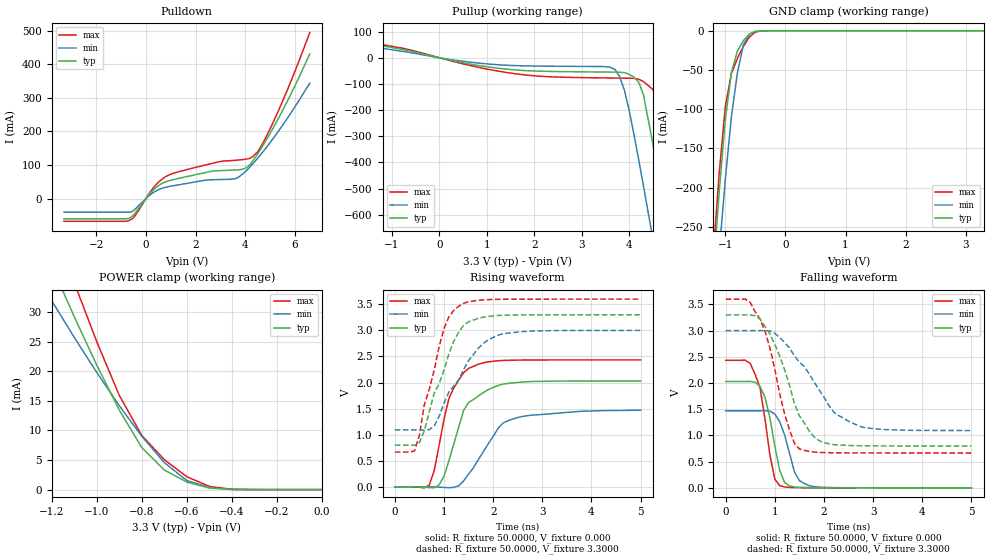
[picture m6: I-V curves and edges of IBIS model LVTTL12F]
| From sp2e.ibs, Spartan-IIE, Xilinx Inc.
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|   Model LVTTL12F
[Model]   LVTTL12F
Model_type   I/O
Polarity   Non-Inverting
Enable   Active-Low
Vinl =   0.800V
Vinh =   2.000V
Vmeas =   1.4000V
Cref =  35.0000pF
Rref =   1.0000M
Vref =  0.000V
C_comp   5.0000pF   4.0000pF   6.0000pF
[Temperature Range]   25.0000   100.0000   0.000
[Voltage Range]   3.3000V   3.0000V   3.6000V
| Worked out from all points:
|   slope of the pulldown table from 0 to 0.495 V, typ, clamps not added: 13 ohm
|   slope of the pullup table from 0 to 0.495 V, typ, clamps not added: 26.2 ohm
|   GND clamp passes 1 mA (typ) near -0.51 V on its own axis
|   POWER clamp passes 1 mA (typ) near -0.57 V on its own axis
|   rising waveform, R_fixture 50.0000, V_fixture 0.000: 20-80 % time 443ps typ, 612ps min, 396ps max; typ from 0 V to 2.03 V
|   rising waveform, R_fixture 50.0000, V_fixture 3.3000: 20-80 % time 541ps typ, 717ps min, 449ps max; typ from 0.798 V to 3.3 V
|   falling waveform, R_fixture 50.0000, V_fixture 0.000: 20-80 % time 257ps typ, 269ps min, 247ps max; typ from 2.03 V to 0 V
|   falling waveform, R_fixture 50.0000, V_fixture 3.3000: 20-80 % time 588ps typ, 843ps min, 461ps max; typ from 3.3 V to 0.799 V
[Pulldown]
| voltage   I(typ)   I(min)   I(max)
-3.3V     -60.15mA   -40.41mA   -67.67mA
-700mV    -58.89mA   -40.41mA   -65.55mA
-500mV    -48.76mA   -35.67mA   -56.93mA
300mV     26mA       18mA       32.25mA
900mV     52.59mA    35.53mA    69.58mA
3.6V      85.3mA     59.32mA    114.1mA
4V        90.58mA    80.11mA    117.1mA
4.3V      111.5mA    103.1mA    124.9mA
4.5V      132.9mA    120.1mA    139mA
5.1V      207mA      176.5mA    223.3mA
5.9V      320.5mA    261.9mA    360.1mA
6.6V      430.7mA    344mA      494.6mA
[Pullup]
| voltage   I(typ)   I(min)   I(max)
-3.3V     107.1mA    98.2mA     107.1mA
1.1V      -36.77mA   -24.77mA   -46.5mA
3.6V      -54.57mA   -35.95mA   -77.25mA
3.8V      -55.05mA   -72.48mA   -77.68mA
4V        -63.12mA   -202mA     -78.1mA
4.2V      -93.01mA   -389.3mA   -81.74mA
4.3V      -141.5mA   -489mA     -90.74mA
4.5V      -329.4mA   -693.2mA   -121.1mA
4.7V      -548.5mA   -901.1mA   -218.8mA
4.9V      -775.5mA   -1.111A    -428mA
5.1V      -1.006A    -1.322A    -657.9mA
6.6V      -2.771A    -2.929A    -2.47A
[GND_clamp]
| voltage   I(typ)   I(min)   I(max)
-3.3V     -2.749A    -2.594A    -2.805A
-1.2V     -306mA     -377.1mA   -282.7mA
-1.1V     -202.5mA   -280mA     -178.8mA
-1V       -112.5mA   -188.5mA   -95.98mA
-900mV    -53.5mA    -109.7mA   -54.53mA
-800mV    -25.67mA   -53.59mA   -35.13mA
-700mV    -12.44mA   -17.88mA   -19.82mA
-600mV    -3.982mA   -4.202mA   -7.865mA
-500mV    -601.5uA   -800.3uA   -1.508mA
-400mV    -51.05uA   -119.3uA   -124.3uA
3.3V      18.74nA    3.634uA    18.92nA
[POWER_clamp]
| voltage   I(typ)   I(min)   I(max)
-3.3V     237mA      175.9mA    284.4mA
-1.3V     46.69mA    38.29mA    56.33mA
-1.2V     37.79mA    31.9mA     45.45mA
-1.1V     29.2mA     25.71mA    34.95mA
-1V       21.01mA    19.78mA    24.97mA
-900mV    13.43mA    14.17mA    15.91mA
-800mV    7.091mA    8.993mA    9.139mA
-700mV    3.305mA    4.554mA    5.052mA
-600mV    1.265mA    1.529mA    2.172mA
-500mV    263.8uA    333.6uA    531.5uA
-400mV    22.63uA    44.12uA    49.77uA
0V        18.8nA     17.88nA    22.53nA
[Ramp]
| variable   typ   min   max
dV/dt_r   1.2180/0.4621n   0.8808/0.6275n   1.4604/0.3920n
dV/dt_f   1.5008/0.5942n   1.1442/0.8735n   1.7606/0.4564n
R_load = 50.0000
[Rising Waveform]
R_fixture = 50.0000
V_fixture = 0.000
| time   V(typ)   V(min)   V(max)
0s        1.805uV    2.104uV    1.747uV
700ps     -15.84mV   19.6uV     30.49mV
800ps     -18.73mV   -2.787mV   307.3mV
900ps     35.45mV    -6.717mV   788.3mV
1.1ns     499.2mV    -18.35mV   1.694V
1.4ns     1.467V     114.6mV    2.189V
1.5ns     1.617V     242.7mV    2.271V
2.1ns     1.944V     1.118V     2.418V
2.3ns     1.983V     1.266V     2.426V
5ns       2.03V      1.468V     2.434V
[Rising Waveform]
R_fixture = 50.0000
V_fixture = 3.3000
V_fixture_min = 3.0000
V_fixture_max = 3.6000
| time   V(typ)   V(min)   V(max)
0s        798mV      1.091V     665.3mV
400ps     796.4mV    1.091V     687.4mV
500ps     845.9mV    1.091V     988.9mV
600ps     1.077V     1.088V     1.575V
800ps     1.794V     1.163V     2.235V
1ns       2.237V     1.603V     3.036V
1.4ns     3.1V       2.249V     3.521V
1.8ns     3.253V     2.751V     3.586V
2.2ns     3.292V     2.934V     3.598V
5ns       3.3V       3V         3.6V
[Falling Waveform]
R_fixture = 50.0000
V_fixture = 0.000
| time   V(typ)   V(min)   V(max)
0s        2.03V      1.471V     2.434V
400ps     2.03V      1.471V     2.435V
600ps     2.014V     1.471V     2.164V
700ps     1.938V     1.471V     1.905V
800ps     1.728V     1.472V     1.313V
1ns       799mV      1.408V     164.7mV
1.1ns     330.1mV    1.262V     41.78mV
1.4ns     15.16mV    298.9mV    5.664mV
1.7ns     5.083mV    42.62mV    2.608mV
5ns       247.7uV    403.5uV    122.9uV
[Falling Waveform]
R_fixture = 50.0000
V_fixture = 3.3000
V_fixture_min = 3.0000
V_fixture_max = 3.6000
| time   V(typ)   V(min)   V(max)
0s        3.3V       3V         3.6V
400ps     3.3V       3V         3.601V
700ps     3.217V     3V         3.221V
900ps     2.931V     2.994V     2.672V
1.2ns     2.248V     2.773V     1.405V
1.5ns     1.376V     2.398V     742.6mV
1.9ns     900.3mV    1.871V     677mV
2.2ns     824.9mV    1.443V     669.1mV
2.7ns     804.3mV    1.185V     666.8mV
5ns       798.7mV    1.093V     665.6mV
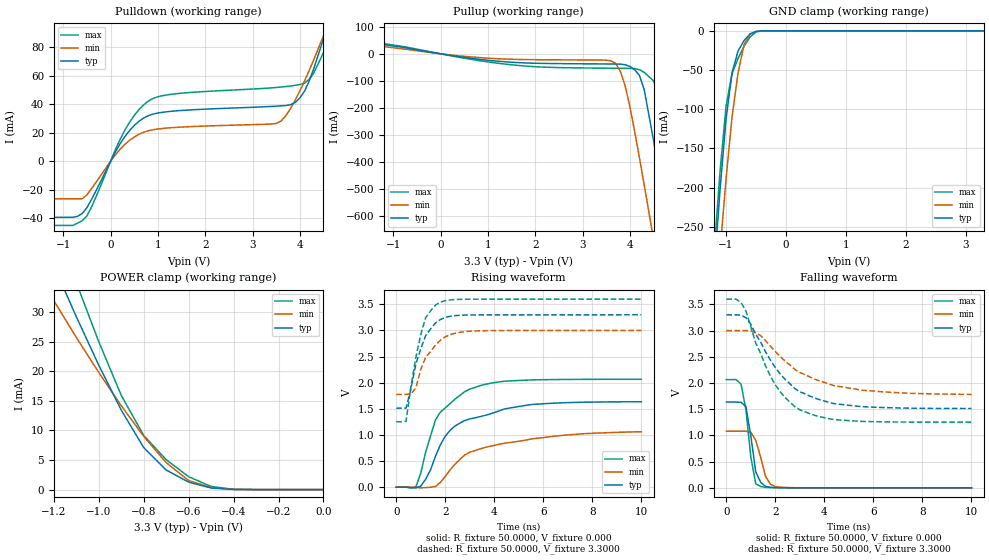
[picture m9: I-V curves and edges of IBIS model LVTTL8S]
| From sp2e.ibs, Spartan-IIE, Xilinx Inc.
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|   Model LVTTL8S
[Model]   LVTTL8S
Model_type   I/O
Polarity   Non-Inverting
Enable   Active-Low
Vinl =   0.800V
Vinh =   2.000V
Vmeas =   1.4000V
Cref =  35.0000pF
Rref =   1.0000M
Vref =  0.000V
C_comp   5.0000pF   4.0000pF   6.0000pF
[Temperature Range]   25.0000   100.0000   0.000
[Voltage Range]   3.3000V   3.0000V   3.6000V
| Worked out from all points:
|   slope of the pulldown table from 0 to 0.495 V, typ, clamps not added: 19.8 ohm
|   slope of the pullup table from 0 to 0.495 V, typ, clamps not added: 37.6 ohm
|   GND clamp passes 1 mA (typ) near -0.51 V on its own axis
|   POWER clamp passes 1 mA (typ) near -0.57 V on its own axis
|   rising waveform, R_fixture 50.0000, V_fixture 0.000: 20-80 % time 1.62ns typ, 2.52ns min, 1.25ns max; typ from 0 V to 1.64 V
|   rising waveform, R_fixture 50.0000, V_fixture 3.3000: 20-80 % time 671ps typ, 802ps min, 591ps max; typ from 1.51 V to 3.3 V
|   falling waveform, R_fixture 50.0000, V_fixture 0.000: 20-80 % time 308ps typ, 375ps min, 334ps max; typ from 1.64 V to 0 V
|   falling waveform, R_fixture 50.0000, V_fixture 3.3000: 20-80 % time 1.69ns typ, 2.2ns min, 1.44ns max; typ from 3.3 V to 1.51 V
[Pulldown]
| voltage   I(typ)   I(min)   I(max)
-3.3V     -39.4mA    -26.4mA    -45.12mA
-800mV    -39.4mA    -26.4mA    -45.12mA
-500mV    -32.62mA   -23.56mA   -38.41mA
300mV     17.27mA    11.77mA    21.73mA
800mV     32.1mA     21.46mA    42.37mA
1.4V      35.46mA    23.84mA    47.52mA
3.5V      38.73mA    26.63mA    51.86mA
3.9V      41.29mA    42.86mA    53.39mA
4.2V      56.65mA    64.01mA    57.69mA
4.5V      86.17mA    88.28mA    76.45mA
4.7V      108.4mA    105.6mA    100mA
6.6V      357.5mA    296.7mA    396mA
[Pullup]
| voltage   I(typ)   I(min)   I(max)
-3.3V     88.6mA     82.8mA     87.5mA
1V        -23.82mA   -16.13mA   -29.99mA
3.6V      -37.7mA    -26.01mA   -53.41mA
3.8V      -38.18mA   -66.39mA   -53.7mA
3.9V      -40.39mA   -120.1mA   -53.85mA
4.2V      -80.09mA   -385.5mA   -58.68mA
4.3V      -132.2mA   -485.2mA   -68.69mA
4.5V      -322.1mA   -689.5mA   -100.2mA
4.7V      -541.6mA   -897.5mA   -206mA
4.9V      -768.7mA   -1.107A    -417.4mA
5.1V      -999.4mA   -1.319A    -647.8mA
6.6V      -2.764A    -2.926A    -2.46A
[GND_clamp]
| voltage   I(typ)   I(min)   I(max)
-3.3V     -2.749A    -2.594A    -2.804A
-1.2V     -306mA     -377.1mA   -282.7mA
-1.1V     -202.5mA   -280mA     -178.8mA
-1V       -112.5mA   -188.5mA   -95.98mA
-900mV    -53.5mA    -109.7mA   -54.53mA
-800mV    -25.67mA   -53.59mA   -35.13mA
-700mV    -12.44mA   -17.88mA   -19.82mA
-600mV    -3.982mA   -4.202mA   -7.865mA
-500mV    -601.5uA   -800.3uA   -1.508mA
-400mV    -51.05uA   -119.3uA   -124.3uA
3.3V      18.74nA    3.634uA    18.92nA
[POWER_clamp]
| voltage   I(typ)   I(min)   I(max)
-3.3V     237mA      175.9mA    284.4mA
-1.3V     46.69mA    38.29mA    56.33mA
-1.2V     37.79mA    31.9mA     45.45mA
-1.1V     29.2mA     25.71mA    34.95mA
-1V       21.01mA    19.78mA    24.97mA
-900mV    13.43mA    14.17mA    15.91mA
-800mV    7.091mA    8.993mA    9.139mA
-700mV    3.305mA    4.554mA    5.052mA
-600mV    1.265mA    1.529mA    2.172mA
-500mV    263.8uA    333.6uA    531.5uA
-400mV    22.63uA    44.12uA    49.77uA
0V        18.8nA     38.36nA    22.53nA
[Ramp]
| variable   typ   min   max
dV/dt_r   0.9810/1.6620n   0.6366/2.5875n   1.2390/1.1845n
dV/dt_f   1.0716/1.6786n   0.7302/2.1970n   1.4082/1.3868n
R_load = 50.0000
[Rising Waveform]
R_fixture = 50.0000
V_fixture = 0.000
| time   V(typ)   V(min)   V(max)
0s        2.224uV    2.595uV    2.141uV
800ps     -12.52mV   -5.336mV   4.282mV
1ns       18.45mV    -12.04mV   265.1mV
1.2ns     151.7mV    -8.508mV   670.3mV
1.6ns     588.6mV    14.18mV    1.287V
2.2ns     1.09V      330.8mV    1.602V
3ns       1.307V     669.8mV    1.877V
4.2ns     1.462V     820.9mV    2.016V
5.6ns     1.585V     929.6mV    2.054V
10ns      1.635V     1.061V     2.065V
[Rising Waveform]
R_fixture = 50.0000
V_fixture = 3.3000
V_fixture_min = 3.0000
V_fixture_max = 3.6000
| time   V(typ)   V(min)   V(max)
0s        1.513V     1.776V     1.252V
400ps     1.512V     1.776V     1.26V
600ps     1.88V      1.783V     1.922V
800ps     2.355V     1.896V     2.48V
1ns       2.646V     2.25V      2.919V
1.2ns     2.9V       2.484V     3.244V
1.8ns     3.209V     2.813V     3.542V
2.2ns     3.272V     2.92V      3.585V
3ns       3.297V     2.986V     3.598V
10ns      3.3V       2.999V     3.6V
[Falling Waveform]
R_fixture = 50.0000
V_fixture = 0.000
| time   V(typ)   V(min)   V(max)
0s        1.637V     1.08V      2.065V
400ps     1.637V     1.08V      2.066V
600ps     1.633V     1.08V      1.977V
800ps     1.551V     1.081V     1.491V
1ns       990.3mV    1.062V     583.9mV
1.2ns     306.2mV    906.8mV    79.03mV
1.4ns     105.5mV    581.7mV    26.33mV
1.6ns     27.38mV    217.1mV    9.177mV
2ns       6.009mV    24.5mV     3.195mV
10ns      146.7uV    152.9uV    84.37uV
[Falling Waveform]
R_fixture = 50.0000
V_fixture = 3.3000
V_fixture_min = 3.0000
V_fixture_max = 3.6000
| time   V(typ)   V(min)   V(max)
0s        3.3V       3V         3.6V
600ps     3.296V     3V         3.534V
800ps     3.245V     3V         3.375V
1ns       3.12V      2.993V     3.07V
1.2ns     2.931V     2.954V     2.762V
1.8ns     2.434V     2.701V     2.129V
2.4ns     2.068V     2.417V     1.722V
3ns       1.833V     2.2V       1.489V
5.6ns     1.547V     1.861V     1.267V
10ns      1.514V     1.783V     1.253V
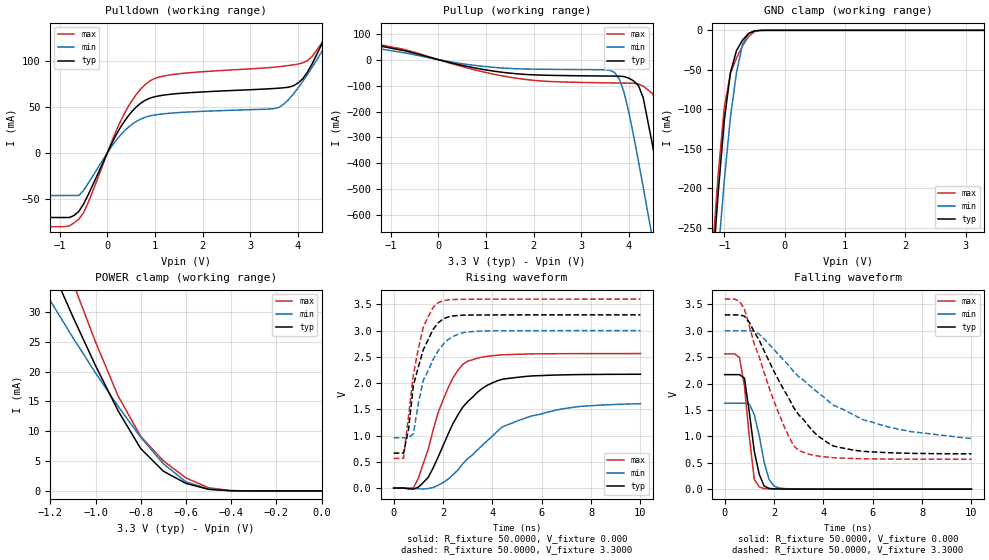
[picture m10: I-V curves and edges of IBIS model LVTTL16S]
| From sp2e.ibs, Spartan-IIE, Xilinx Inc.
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|   Model LVTTL16S
[Model]   LVTTL16S
Model_type   I/O
Polarity   Non-Inverting
Enable   Active-Low
Vinl =   0.800V
Vinh =   2.000V
Vmeas =   1.4000V
Cref =  35.0000pF
Rref =   1.0000M
Vref =  0.000V
C_comp   5.0000pF   4.0000pF   6.0000pF
[Temperature Range]   25.0000   100.0000   0.000
[Voltage Range]   3.3000V   3.0000V   3.6000V
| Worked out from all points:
|   slope of the pulldown table from 0 to 0.495 V, typ, clamps not added: 11.3 ohm
|   slope of the pullup table from 0 to 0.495 V, typ, clamps not added: 22.7 ohm
|   GND clamp passes 1 mA (typ) near -0.51 V on its own axis
|   POWER clamp passes 1 mA (typ) near -0.57 V on its own axis
|   rising waveform, R_fixture 50.0000, V_fixture 0.000: 20-80 % time 1.56ns typ, 2.5ns min, 1.12ns max; typ from 0 V to 2.17 V
|   rising waveform, R_fixture 50.0000, V_fixture 3.3000: 20-80 % time 725ps typ, 858ps min, 614ps max; typ from 0.666 V to 3.3 V
|   falling waveform, R_fixture 50.0000, V_fixture 0.000: 20-80 % time 418ps typ, 459ps min, 354ps max; typ from 2.17 V to 0 V
|   falling waveform, R_fixture 50.0000, V_fixture 3.3000: 20-80 % time 1.95ns typ, 3.28ns min, 1.37ns max; typ from 3.3 V to 0.669 V
[Pulldown]
| voltage   I(typ)   I(min)   I(max)
-3.3V     -70.66mA   -46.65mA   -80.67mA
-700mV    -68.43mA   -46.65mA   -76.48mA
-500mV    -55.91mA   -40.95mA   -65.29mA
400mV     37.55mA    25.93mA    46.88mA
700mV     54.05mA    36.76mA    69.52mA
1V        61.15mA    41.22mA    81.1mA
3.6V      70.43mA    49.47mA    93.83mA
4.1V      80.53mA    77.58mA    97.93mA
4.3V      97.01mA    93.21mA    105mA
4.7V      141.4mA    127.9mA    144.1mA
4.9V      166mA      146.6mA    172.8mA
6.6V      410.5mA    330.4mA    469.3mA
[Pullup]
| voltage   I(typ)   I(min)   I(max)
-3.3V     116.8mA    106.3mA    117.5mA
1.2V      -45.24mA   -30.27mA   -57.51mA
3.6V      -63.32mA   -41.14mA   -89.59mA
3.8V      -63.82mA   -75.74mA   -90.08mA
3.9V      -65.44mA   -127.4mA   -90.31mA
4.2V      -99.96mA   -391.3mA   -93.78mA
4.3V      -146.5mA   -490.9mA   -102.2mA
4.5V      -333.2mA   -695.1mA   -132.1mA
4.7V      -552mA     -903mA     -225.7mA
4.9V      -779mA     -1.113A    -433.5mA
5.1V      -1.009A    -1.324A    -663.2mA
6.6V      -2.775A    -2.931A    -2.475A
[GND_clamp]
| voltage   I(typ)   I(min)   I(max)
-3.3V     -2.749A    -2.594A    -2.805A
-1.2V     -306mA     -377.1mA   -282.7mA
-1.1V     -202.5mA   -280mA     -178.8mA
-1V       -112.5mA   -188.5mA   -95.98mA
-900mV    -53.5mA    -109.7mA   -54.53mA
-800mV    -25.67mA   -53.59mA   -35.13mA
-700mV    -12.44mA   -17.88mA   -19.82mA
-600mV    -3.982mA   -4.202mA   -7.865mA
-500mV    -601.5uA   -800.3uA   -1.508mA
-400mV    -51.05uA   -119.3uA   -124.3uA
3.3V      18.74nA    3.634uA    18.92nA
[POWER_clamp]
| voltage   I(typ)   I(min)   I(max)
-3.3V     237mA      175.9mA    284.4mA
-1.3V     46.69mA    38.29mA    56.33mA
-1.2V     37.79mA    31.9mA     45.45mA
-1.1V     29.2mA     25.71mA    34.95mA
-1V       21.01mA    19.78mA    24.97mA
-900mV    13.43mA    14.17mA    15.91mA
-800mV    7.091mA    8.993mA    9.139mA
-700mV    3.305mA    4.554mA    5.052mA
-600mV    1.265mA    1.529mA    2.172mA
-500mV    263.8uA    333.6uA    531.5uA
-400mV    22.63uA    44.12uA    49.77uA
0V        18.8nA     38.3nA     22.53nA
[Ramp]
| variable   typ   min   max
dV/dt_r   1.3008/1.5553n   0.9642/2.4921n   1.5372/1.0670n
dV/dt_f   1.5787/1.9536n   1.2001/3.1912n   1.8204/1.3154n
R_load = 50.0000
[Rising Waveform]
R_fixture = 50.0000
V_fixture = 0.000
| time   V(typ)   V(min)   V(max)
0s        1.565uV    1.815uV    1.522uV
800ps     -20.61mV   -3.077mV   4.223mV
1.4ns     205mV      -9.034mV   736.4mV
1.8ns     588.3mV    53.46mV    1.433V
2.2ns     1.02V      168.2mV    1.899V
2.6ns     1.391V     342.4mV    2.24V
3ns       1.647V     561.3mV    2.416V
4.2ns     2.043V     1.082V     2.531V
5.6ns     2.136V     1.373V     2.555V
10ns      2.168V     1.607V     2.562V
[Rising Waveform]
R_fixture = 50.0000
V_fixture = 3.3000
V_fixture_min = 3.0000
V_fixture_max = 3.6000
| time   V(typ)   V(min)   V(max)
0s        666.2mV    958.1mV    565.5mV
400ps     665.7mV    958.2mV    568.9mV
600ps     1.112V     957.8mV    1.362V
800ps     1.956V     1.035V     2.167V
1.2ns     2.633V     2.054V     3.063V
1.6ns     3.023V     2.449V     3.442V
1.8ns     3.146V     2.612V     3.53V
2.4ns     3.277V     2.886V     3.591V
3ns       3.295V     2.974V     3.596V
10ns      3.3V       2.999V     3.6V
[Falling Waveform]
R_fixture = 50.0000
V_fixture = 0.000
| time   V(typ)   V(min)   V(max)
0s        2.169V     1.627V     2.562V
600ps     2.169V     1.627V     2.493V
800ps     2.102V     1.628V     1.951V
1ns       1.447V     1.61V      985.2mV
1.2ns     715.7mV    1.409V     184mV
1.4ns     280.9mV    1.012V     43.42mV
1.6ns     58.04mV    508.7mV    9.87mV
1.8ns     14.69mV    184mV      5.394mV
2.2ns     4.424mV    23.52mV    2.301mV
10ns      82.54uV    150.6uV    57.71uV
[Falling Waveform]
R_fixture = 50.0000
V_fixture = 3.3000
V_fixture_min = 3.0000
V_fixture_max = 3.6000
| time   V(typ)   V(min)   V(max)
0s        3.3V       3V         3.6V
800ps     3.276V     3V         3.409V
1.4ns     2.821V     2.935V     2.506V
2ns       2.232V     2.643V     1.663V
2.6ns     1.722V     2.341V     995.5mV
3ns       1.408V     2.129V     733.6mV
3.8ns     1V         1.822V     626.9mV
4.6ns     795.9mV    1.55V      591.8mV
6.8ns     688mV      1.161V     569.8mV
10ns      668.9mV    960mV      566mV
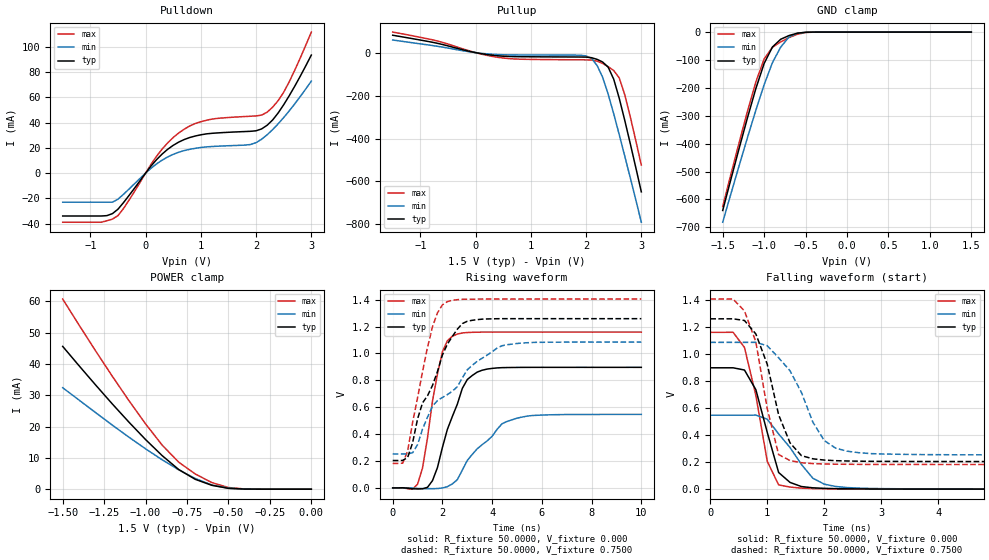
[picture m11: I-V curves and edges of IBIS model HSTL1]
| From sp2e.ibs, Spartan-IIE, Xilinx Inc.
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|   Model HSTL1
[Model]   HSTL1
Model_type   I/O
Polarity   Non-Inverting
Enable   Active-Low
Vinl =   0.650V
Vinh =   0.850V
Vmeas =   0.7500V
Cref =  20.0000pF
Rref =  50.0000
Vref =   0.7500V
C_comp   5.0000pF   4.0000pF   6.0000pF
[Temperature Range]   25.0000   100.0000   0.000
[Voltage Range]   1.5000V   1.4000V   1.6000V
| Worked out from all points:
|   slope of the pulldown table from 0 to 0.225 V, typ, clamps not added: 19 ohm
|   slope of the pullup table from 0 to 0.225 V, typ, clamps not added: 23.5 ohm
|   GND clamp passes 1 mA (typ) near -0.51 V on its own axis
|   POWER clamp passes 1 mA (typ) near -0.58 V on its own axis
|   rising waveform, R_fixture 50.0000, V_fixture 0.000: 20-80 % time 924ps typ, 1.47ns min, 622ps max; typ from 0 V to 0.897 V
|   rising waveform, R_fixture 50.0000, V_fixture 0.7500: 20-80 % time 1.26ns typ, 2.07ns min, 806ps max; typ from 0.204 V to 1.26 V
|   falling waveform, R_fixture 50.0000, V_fixture 0.000: 20-80 % time 351ps typ, 597ps min, 322ps max; typ from 0.897 V to 0 V
|   falling waveform, R_fixture 50.0000, V_fixture 0.7500: 20-80 % time 441ps typ, 603ps min, 362ps max; typ from 1.26 V to 0.204 V
[Pulldown]
| voltage   I(typ)   I(min)   I(max)
-1.5V     -33.98mA   -23.03mA   -38.89mA
-700mV    -33.69mA   -23.03mA   -37.75mA
-500mV    -28.61mA   -20.64mA   -33.68mA
300mV     15.14mA    10.3mA     19.08mA
500mV     22.03mA    14.9mA     28.23mA
800mV     28.24mA    18.88mA    37.42mA
1.2V      31.55mA    21.09mA    42.82mA
1.9V      33.15mA    22.7mA     45.09mA
2.2V      37.95mA    30.38mA    48.28mA
2.5V      54.22mA    44.05mA    64.14mA
2.7V      68.9mA     54.92mA    81.57mA
3V        93.58mA    72.95mA    111.8mA
[Pullup]
| voltage   I(typ)   I(min)   I(max)
-1.5V     80.99mA    58.81mA    95.66mA
-700mV    43.92mA    29.88mA    54.7mA
400mV     -14.75mA   -8.945mA   -21.71mA
1.9V      -20.46mA   -12.26mA   -33.54mA
2.1V      -23.68mA   -26.88mA   -34.7mA
2.2V      -31.41mA   -60.03mA   -39.61mA
2.3V      -43.82mA   -115mA     -50.52mA
2.4V      -67.75mA   -193.4mA   -65.34mA
2.5V      -123.4mA   -284.7mA   -83.26mA
2.6V      -212.2mA   -381.6mA   -117.7mA
2.7V      -315.2mA   -481.5mA   -196.1mA
3V        -648.4mA   -789.7mA   -524mA
[GND_clamp]
| voltage   I(typ)   I(min)   I(max)
-1.5V     -639.4mA   -681.4mA   -625.3mA
-1.3V     -414.8mA   -476.9mA   -394mA
-1.2V     -306mA     -377mA     -282.7mA
-1.1V     -202.5mA   -280mA     -178.7mA
-1V       -112.5mA   -188.5mA   -95.97mA
-900mV    -53.49mA   -109.7mA   -54.51mA
-800mV    -25.66mA   -53.59mA   -35.12mA
-700mV    -12.43mA   -17.88mA   -19.81mA
-600mV    -3.981mA   -4.201mA   -7.863mA
-500mV    -601.5uA   -800.2uA   -1.508mA
-400mV    -51.04uA   -119.3uA   -124.3uA
1.5V      8.586nA    31.4nA     8.324nA
[POWER_clamp]
| voltage   I(typ)   I(min)   I(max)
-1.5V     45.61mA    32.41mA    60.74mA
-1.3V     33.2mA     24.4mA     44.06mA
-1.1V     21.39mA    16.59mA    28.25mA
-1V       15.85mA    12.89mA    20.86mA
-900mV    10.72mA    9.386mA    14.08mA
-800mV    6.271mA    6.174mA    8.616mA
-700mV    3.136mA    3.398mA    4.838mA
-600mV    1.222mA    1.343mA    2.099mA
-500mV    258.2uA    323.8uA    517.7uA
-400mV    22.21uA    43.58uA    48.44uA
0V        8.586nA    20.17nA    9.284nA
[Ramp]
| variable   typ   min   max
dV/dt_r   0.5383/0.9513n   0.3280/1.4716n   0.6954/0.5806n
dV/dt_f   0.6244/0.4843n   0.4895/0.7549n   0.7198/0.3797n
R_load = 50.0000
[Rising Waveform]
R_fixture = 50.0000
V_fixture = 0.000
| time   V(typ)   V(min)   V(max)
0s        0V         0V         0V
1ns       -7.91mV    -4.092mV   27.41mV
1.2ns     -6.536mV   -5.441mV   148.6mV
1.6ns     53.88mV    -5.854mV   646.5mV
2ns       301.4mV    -728.7uV   1.013V
2.4ns     531.9mV    29.69mV    1.129V
3ns       806.2mV    204.2mV    1.156V
3.6ns     875.6mV    322mV      1.159V
4.6ns     895.4mV    494.4mV    1.159V
10ns      897.1mV    546.7mV    1.159V
[Rising Waveform]
R_fixture = 50.0000
V_fixture = 0.7500
V_fixture_min = 0.7000
V_fixture_max = 0.8000
| time   V(typ)   V(min)   V(max)
0s        203.6mV    252.4mV    181.9mV
400ps     204.4mV    252.6mV    183.9mV
600ps     226.1mV    252.9mV    273mV
1ns       513.3mV    321.9mV    670.5mV
1.4ns     685.4mV    526.7mV    1.047V
1.6ns     761.9mV    608.1mV    1.198V
2ns       989.2mV    673.3mV    1.362V
2.8ns     1.222V     818.6mV    1.403V
4.4ns     1.259V     1.058V     1.405V
10ns      1.259V     1.085V     1.405V
[Falling Waveform]
R_fixture = 50.0000
V_fixture = 0.000
| time   V(typ)   V(min)   V(max)
0s        897.1mV    546.7mV    1.159V
400ps     897.1mV    546.7mV    1.159V
600ps     880.6mV    546.7mV    1.048V
800ps     735.4mV    547.2mV    693mV
1ns       419.5mV    517.3mV    206.2mV
1.2ns     123.2mV    408.4mV    31.38mV
1.4ns     49.89mV    307.7mV    15.6mV
1.8ns     10.11mV    80.83mV    4.516mV
2.2ns     4.035mV    20.11mV    2.004mV
10ns      159.4uV    271.7uV    118.2uV
[Falling Waveform]
R_fixture = 50.0000
V_fixture = 0.7500
V_fixture_min = 0.7000
V_fixture_max = 0.8000
| time   V(typ)   V(min)   V(max)
0s        1.259V     1.085V     1.405V
400ps     1.259V     1.085V     1.405V
600ps     1.247V     1.085V     1.317V
800ps     1.147V     1.085V     1.089V
1ns       923mV      1.06V      594.4mV
1.2ns     549.1mV    970.7mV    255.6mV
1.4ns     342.1mV    875mV      211.5mV
2ns       215.1mV    359.3mV    186.2mV
2.4ns     208.3mV    281mV      183.9mV
10ns      203.8mV    252.8mV    182.1mV
